VERSION 5.7 ;
  NOWIREEXTENSIONATPIN ON ;
  DIVIDERCHAR "/" ;
  BUSBITCHARS "[]" ;
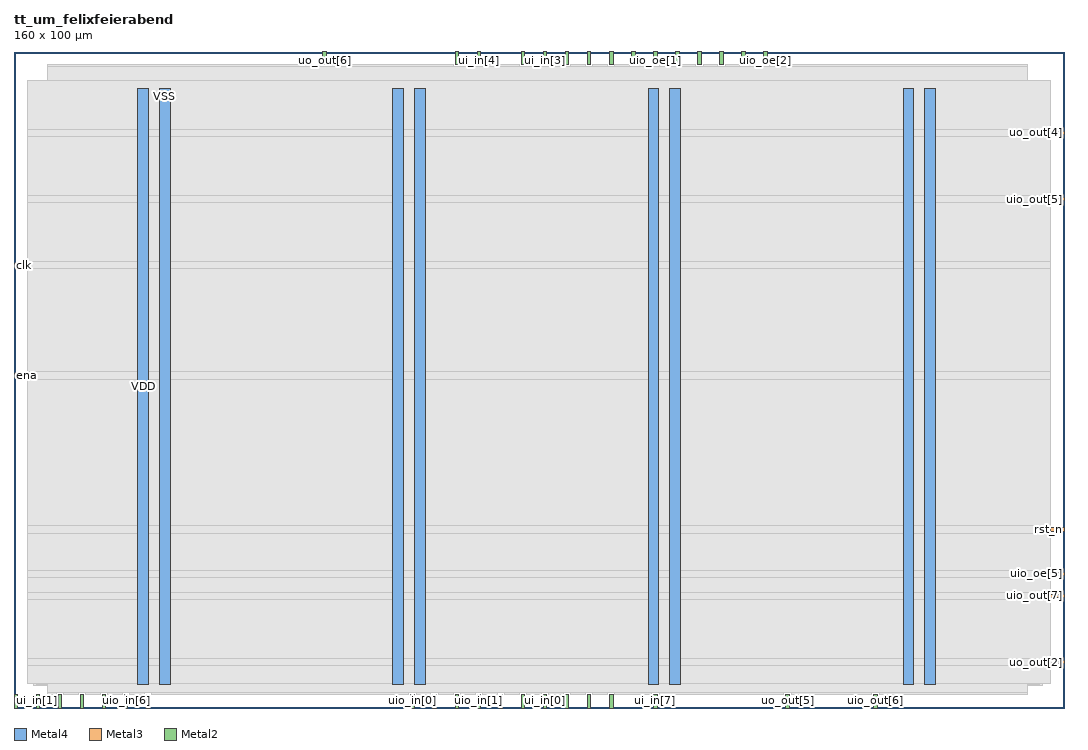
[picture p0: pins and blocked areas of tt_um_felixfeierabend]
MACRO tt_um_felixfeierabend
  CLASS BLOCK ;
  FOREIGN tt_um_felixfeierabend ;
  ORIGIN 0.000 0.000 ;
  SIZE 160.000 BY 100.000 ;
  PIN VDD
    DIRECTION INOUT ;
    USE POWER ;
    PORT
      LAYER Metal4 ;
        RECT 18.880 3.620 20.480 94.380 ;
    END
    PORT
      LAYER Metal4 ;
        RECT 57.750 3.620 59.350 94.380 ;
    END
    PORT
      LAYER Metal4 ;
        RECT 96.620 3.620 98.220 94.380 ;
    END
    PORT
      LAYER Metal4 ;
        RECT 135.490 3.620 137.090 94.380 ;
    END
  END VDD
  PIN VSS
    DIRECTION INOUT ;
    USE GROUND ;
    PORT
      LAYER Metal4 ;
        RECT 22.180 3.620 23.780 94.380 ;
    END
    PORT
      LAYER Metal4 ;
        RECT 61.050 3.620 62.650 94.380 ;
    END
    PORT
      LAYER Metal4 ;
        RECT 99.920 3.620 101.520 94.380 ;
    END
    PORT
      LAYER Metal4 ;
        RECT 138.790 3.620 140.390 94.380 ;
    END
  END VSS
  PIN clk
    DIRECTION INPUT ;
    USE SIGNAL ;
    ANTENNAGATEAREA 4.738000 ;
    PORT
      LAYER Metal3 ;
        RECT 0.000 67.200 2.000 67.760 ;
    END
  END clk
  PIN ena
    DIRECTION INPUT ;
    USE SIGNAL ;
    ANTENNAGATEAREA 0.741000 ;
    PORT
      LAYER Metal3 ;
        RECT 0.000 50.400 2.000 50.960 ;
    END
  END ena
  PIN rst_n
    DIRECTION INPUT ;
    USE SIGNAL ;
    ANTENNAGATEAREA 0.726000 ;
    PORT
      LAYER Metal3 ;
        RECT 158.000 26.880 160.000 27.440 ;
    END
  END rst_n
  PIN ui_in[0]
    DIRECTION INPUT ;
    USE SIGNAL ;
    ANTENNAGATEAREA 0.741000 ;
    PORT
      LAYER Metal2 ;
        RECT 80.640 0.000 81.200 2.000 ;
    END
  END ui_in[0]
  PIN ui_in[1]
    DIRECTION INPUT ;
    USE SIGNAL ;
    PORT
      LAYER Metal2 ;
        RECT 0.000 0.000 0.560 2.000 ;
    END
  END ui_in[1]
  PIN ui_in[2]
    DIRECTION INPUT ;
    USE SIGNAL ;
    PORT
      LAYER Metal2 ;
        RECT 3.360 0.000 3.920 2.000 ;
    END
  END ui_in[2]
  PIN ui_in[3]
    DIRECTION INPUT ;
    USE SIGNAL ;
    ANTENNAGATEAREA 0.741000 ;
    PORT
      LAYER Metal2 ;
        RECT 80.640 98.000 81.200 100.000 ;
    END
  END ui_in[3]
  PIN ui_in[4]
    DIRECTION INPUT ;
    USE SIGNAL ;
    ANTENNAGATEAREA 0.741000 ;
    PORT
      LAYER Metal2 ;
        RECT 70.560 98.000 71.120 100.000 ;
    END
  END ui_in[4]
  PIN ui_in[5]
    DIRECTION INPUT ;
    USE SIGNAL ;
    ANTENNAGATEAREA 0.741000 ;
    PORT
      LAYER Metal2 ;
        RECT 77.280 98.000 77.840 100.000 ;
    END
  END ui_in[5]
  PIN ui_in[6]
    DIRECTION INPUT ;
    USE SIGNAL ;
    ANTENNAGATEAREA 0.741000 ;
    PORT
      LAYER Metal2 ;
        RECT 84.000 98.000 84.560 100.000 ;
    END
  END ui_in[6]
  PIN ui_in[7]
    DIRECTION INPUT ;
    USE SIGNAL ;
    ANTENNAGATEAREA 0.741000 ;
    PORT
      LAYER Metal2 ;
        RECT 97.440 0.000 98.000 2.000 ;
    END
  END ui_in[7]
  PIN uio_in[0]
    DIRECTION INPUT ;
    USE SIGNAL ;
    ANTENNAGATEAREA 0.741000 ;
    PORT
      LAYER Metal2 ;
        RECT 60.480 0.000 61.040 2.000 ;
    END
  END uio_in[0]
  PIN uio_in[1]
    DIRECTION INPUT ;
    USE SIGNAL ;
    ANTENNAGATEAREA 0.726000 ;
    PORT
      LAYER Metal2 ;
        RECT 70.560 0.000 71.120 2.000 ;
    END
  END uio_in[1]
  PIN uio_in[2]
    DIRECTION INPUT ;
    USE SIGNAL ;
    ANTENNAGATEAREA 0.741000 ;
    PORT
      LAYER Metal2 ;
        RECT 63.840 0.000 64.400 2.000 ;
    END
  END uio_in[2]
  PIN uio_in[3]
    DIRECTION INPUT ;
    USE SIGNAL ;
    PORT
      LAYER Metal2 ;
        RECT 6.720 0.000 7.280 2.000 ;
    END
  END uio_in[3]
  PIN uio_in[4]
    DIRECTION INPUT ;
    USE SIGNAL ;
    PORT
      LAYER Metal2 ;
        RECT 10.080 0.000 10.640 2.000 ;
    END
  END uio_in[4]
  PIN uio_in[5]
    DIRECTION INPUT ;
    USE SIGNAL ;
    PORT
      LAYER Metal2 ;
        RECT 13.440 0.000 14.000 2.000 ;
    END
  END uio_in[5]
  PIN uio_in[6]
    DIRECTION INPUT ;
    USE SIGNAL ;
    PORT
      LAYER Metal2 ;
        RECT 16.800 0.000 17.360 2.000 ;
    END
  END uio_in[6]
  PIN uio_in[7]
    DIRECTION INPUT ;
    USE SIGNAL ;
    PORT
      LAYER Metal2 ;
        RECT 20.160 0.000 20.720 2.000 ;
    END
  END uio_in[7]
  PIN uio_oe[0]
    DIRECTION OUTPUT ;
    USE SIGNAL ;
    ANTENNADIFFAREA 0.536800 ;
    PORT
      LAYER Metal2 ;
        RECT 87.360 98.000 87.920 100.000 ;
    END
  END uio_oe[0]
  PIN uio_oe[1]
    DIRECTION OUTPUT ;
    USE SIGNAL ;
    ANTENNADIFFAREA 0.536800 ;
    PORT
      LAYER Metal2 ;
        RECT 97.440 98.000 98.000 100.000 ;
    END
  END uio_oe[1]
  PIN uio_oe[2]
    DIRECTION OUTPUT ;
    USE SIGNAL ;
    ANTENNADIFFAREA 0.536800 ;
    PORT
      LAYER Metal2 ;
        RECT 114.240 98.000 114.800 100.000 ;
    END
  END uio_oe[2]
  PIN uio_oe[3]
    DIRECTION OUTPUT ;
    USE SIGNAL ;
    ANTENNADIFFAREA 0.360800 ;
    PORT
      LAYER Metal2 ;
        RECT 77.280 0.000 77.840 2.000 ;
    END
  END uio_oe[3]
  PIN uio_oe[4]
    DIRECTION OUTPUT ;
    USE SIGNAL ;
    ANTENNADIFFAREA 0.360800 ;
    PORT
      LAYER Metal2 ;
        RECT 110.880 98.000 111.440 100.000 ;
    END
  END uio_oe[4]
  PIN uio_oe[5]
    DIRECTION OUTPUT ;
    USE SIGNAL ;
    ANTENNADIFFAREA 0.360800 ;
    PORT
      LAYER Metal3 ;
        RECT 158.000 20.160 160.000 20.720 ;
    END
  END uio_oe[5]
  PIN uio_oe[6]
    DIRECTION OUTPUT ;
    USE SIGNAL ;
    ANTENNADIFFAREA 0.360800 ;
    PORT
      LAYER Metal2 ;
        RECT 73.920 0.000 74.480 2.000 ;
    END
  END uio_oe[6]
  PIN uio_oe[7]
    DIRECTION OUTPUT ;
    USE SIGNAL ;
    ANTENNADIFFAREA 0.360800 ;
    PORT
      LAYER Metal2 ;
        RECT 104.160 98.000 104.720 100.000 ;
    END
  END uio_oe[7]
  PIN uio_out[0]
    DIRECTION OUTPUT ;
    USE SIGNAL ;
    ANTENNADIFFAREA 0.360800 ;
    PORT
      LAYER Metal2 ;
        RECT 107.520 98.000 108.080 100.000 ;
    END
  END uio_out[0]
  PIN uio_out[1]
    DIRECTION OUTPUT ;
    USE SIGNAL ;
    ANTENNADIFFAREA 0.360800 ;
    PORT
      LAYER Metal2 ;
        RECT 87.360 0.000 87.920 2.000 ;
    END
  END uio_out[1]
  PIN uio_out[2]
    DIRECTION OUTPUT ;
    USE SIGNAL ;
    ANTENNADIFFAREA 0.360800 ;
    PORT
      LAYER Metal2 ;
        RECT 100.800 98.000 101.360 100.000 ;
    END
  END uio_out[2]
  PIN uio_out[3]
    DIRECTION OUTPUT ;
    USE SIGNAL ;
    ANTENNADIFFAREA 0.360800 ;
    PORT
      LAYER Metal2 ;
        RECT 67.200 0.000 67.760 2.000 ;
    END
  END uio_out[3]
  PIN uio_out[4]
    DIRECTION OUTPUT ;
    USE SIGNAL ;
    ANTENNADIFFAREA 0.360800 ;
    PORT
      LAYER Metal2 ;
        RECT 90.720 0.000 91.280 2.000 ;
    END
  END uio_out[4]
  PIN uio_out[5]
    DIRECTION OUTPUT ;
    USE SIGNAL ;
    ANTENNADIFFAREA 0.360800 ;
    PORT
      LAYER Metal3 ;
        RECT 158.000 77.280 160.000 77.840 ;
    END
  END uio_out[5]
  PIN uio_out[6]
    DIRECTION OUTPUT ;
    USE SIGNAL ;
    ANTENNADIFFAREA 0.360800 ;
    PORT
      LAYER Metal2 ;
        RECT 131.040 0.000 131.600 2.000 ;
    END
  END uio_out[6]
  PIN uio_out[7]
    DIRECTION OUTPUT ;
    USE SIGNAL ;
    ANTENNADIFFAREA 0.360800 ;
    PORT
      LAYER Metal3 ;
        RECT 158.000 16.800 160.000 17.360 ;
    END
  END uio_out[7]
  PIN uo_out[0]
    DIRECTION OUTPUT ;
    USE SIGNAL ;
    ANTENNADIFFAREA 1.986000 ;
    PORT
      LAYER Metal2 ;
        RECT 84.000 0.000 84.560 2.000 ;
    END
  END uo_out[0]
  PIN uo_out[1]
    DIRECTION OUTPUT ;
    USE SIGNAL ;
    ANTENNADIFFAREA 0.360800 ;
    PORT
      LAYER Metal2 ;
        RECT 90.720 98.000 91.280 100.000 ;
    END
  END uo_out[1]
  PIN uo_out[2]
    DIRECTION OUTPUT ;
    USE SIGNAL ;
    ANTENNADIFFAREA 0.360800 ;
    PORT
      LAYER Metal3 ;
        RECT 158.000 6.720 160.000 7.280 ;
    END
  END uo_out[2]
  PIN uo_out[3]
    DIRECTION OUTPUT ;
    USE SIGNAL ;
    ANTENNADIFFAREA 0.360800 ;
    PORT
      LAYER Metal2 ;
        RECT 67.200 98.000 67.760 100.000 ;
    END
  END uo_out[3]
  PIN uo_out[4]
    DIRECTION OUTPUT ;
    USE SIGNAL ;
    ANTENNADIFFAREA 0.360800 ;
    PORT
      LAYER Metal3 ;
        RECT 158.000 87.360 160.000 87.920 ;
    END
  END uo_out[4]
  PIN uo_out[5]
    DIRECTION OUTPUT ;
    USE SIGNAL ;
    ANTENNADIFFAREA 0.360800 ;
    PORT
      LAYER Metal2 ;
        RECT 117.600 0.000 118.160 2.000 ;
    END
  END uo_out[5]
  PIN uo_out[6]
    DIRECTION OUTPUT ;
    USE SIGNAL ;
    ANTENNADIFFAREA 0.360800 ;
    PORT
      LAYER Metal2 ;
        RECT 47.040 98.000 47.600 100.000 ;
    END
  END uo_out[6]
  PIN uo_out[7]
    DIRECTION OUTPUT ;
    USE SIGNAL ;
    ANTENNADIFFAREA 0.360800 ;
    PORT
      LAYER Metal2 ;
        RECT 94.080 98.000 94.640 100.000 ;
    END
  END uo_out[7]
  OBS
      LAYER Nwell ;
        RECT 2.930 3.490 156.670 94.510 ;
      LAYER Metal1 ;
        RECT 3.360 3.620 156.240 94.380 ;
      LAYER Metal2 ;
        RECT 5.180 97.700 46.740 98.000 ;
        RECT 47.900 97.700 66.900 98.000 ;
        RECT 68.060 97.700 70.260 98.000 ;
        RECT 71.420 97.700 76.980 98.000 ;
        RECT 78.140 97.700 80.340 98.000 ;
        RECT 81.500 97.700 83.700 98.000 ;
        RECT 84.860 97.700 87.060 98.000 ;
        RECT 88.220 97.700 90.420 98.000 ;
        RECT 91.580 97.700 93.780 98.000 ;
        RECT 94.940 97.700 97.140 98.000 ;
        RECT 98.300 97.700 100.500 98.000 ;
        RECT 101.660 97.700 103.860 98.000 ;
        RECT 105.020 97.700 107.220 98.000 ;
        RECT 108.380 97.700 110.580 98.000 ;
        RECT 111.740 97.700 113.940 98.000 ;
        RECT 115.100 97.700 154.420 98.000 ;
        RECT 5.180 2.300 154.420 97.700 ;
        RECT 5.180 2.000 6.420 2.300 ;
        RECT 7.580 2.000 9.780 2.300 ;
        RECT 10.940 2.000 13.140 2.300 ;
        RECT 14.300 2.000 16.500 2.300 ;
        RECT 17.660 2.000 19.860 2.300 ;
        RECT 21.020 2.000 60.180 2.300 ;
        RECT 61.340 2.000 63.540 2.300 ;
        RECT 64.700 2.000 66.900 2.300 ;
        RECT 68.060 2.000 70.260 2.300 ;
        RECT 71.420 2.000 73.620 2.300 ;
        RECT 74.780 2.000 76.980 2.300 ;
        RECT 78.140 2.000 80.340 2.300 ;
        RECT 81.500 2.000 83.700 2.300 ;
        RECT 84.860 2.000 87.060 2.300 ;
        RECT 88.220 2.000 90.420 2.300 ;
        RECT 91.580 2.000 97.140 2.300 ;
        RECT 98.300 2.000 117.300 2.300 ;
        RECT 118.460 2.000 130.740 2.300 ;
        RECT 131.900 2.000 154.420 2.300 ;
      LAYER Metal3 ;
        RECT 2.000 88.220 158.000 95.620 ;
        RECT 2.000 87.060 157.700 88.220 ;
        RECT 2.000 78.140 158.000 87.060 ;
        RECT 2.000 76.980 157.700 78.140 ;
        RECT 2.000 68.060 158.000 76.980 ;
        RECT 2.300 66.900 158.000 68.060 ;
        RECT 2.000 51.260 158.000 66.900 ;
        RECT 2.300 50.100 158.000 51.260 ;
        RECT 2.000 27.740 158.000 50.100 ;
        RECT 2.000 26.580 157.700 27.740 ;
        RECT 2.000 21.020 158.000 26.580 ;
        RECT 2.000 19.860 157.700 21.020 ;
        RECT 2.000 17.660 158.000 19.860 ;
        RECT 2.000 16.500 157.700 17.660 ;
        RECT 2.000 7.580 158.000 16.500 ;
        RECT 2.000 6.420 157.700 7.580 ;
        RECT 2.000 3.780 158.000 6.420 ;
  END
END tt_um_felixfeierabend
END LIBRARY

